VERSION 5.8 ;
BUSBITCHARS "[]" ;
DIVIDERCHAR "/" ;
UNITS
  DATABASE MICRONS 1000 ;
END UNITS

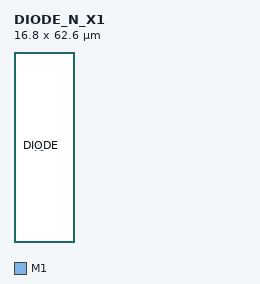
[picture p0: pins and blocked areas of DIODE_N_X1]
MACRO DIODE_N_X1
  CLASS CORE ANTENNACELL ;
  ORIGIN 0 0 ;
  SIZE 16.800 BY 62.600 ;
  SYMMETRY X Y ;
  SITE TR1um_site ;
  PIN DIODE
    DIRECTION INPUT ;
    USE SIGNAL ;
    ANTENNADIFFAREA 21.600 ;
    PORT
      LAYER M1 ;
        RECT 7.200 30.000 10.800 33.600 ;
    END
  END DIODE
END DIODE_N_X1
END LIBRARY
